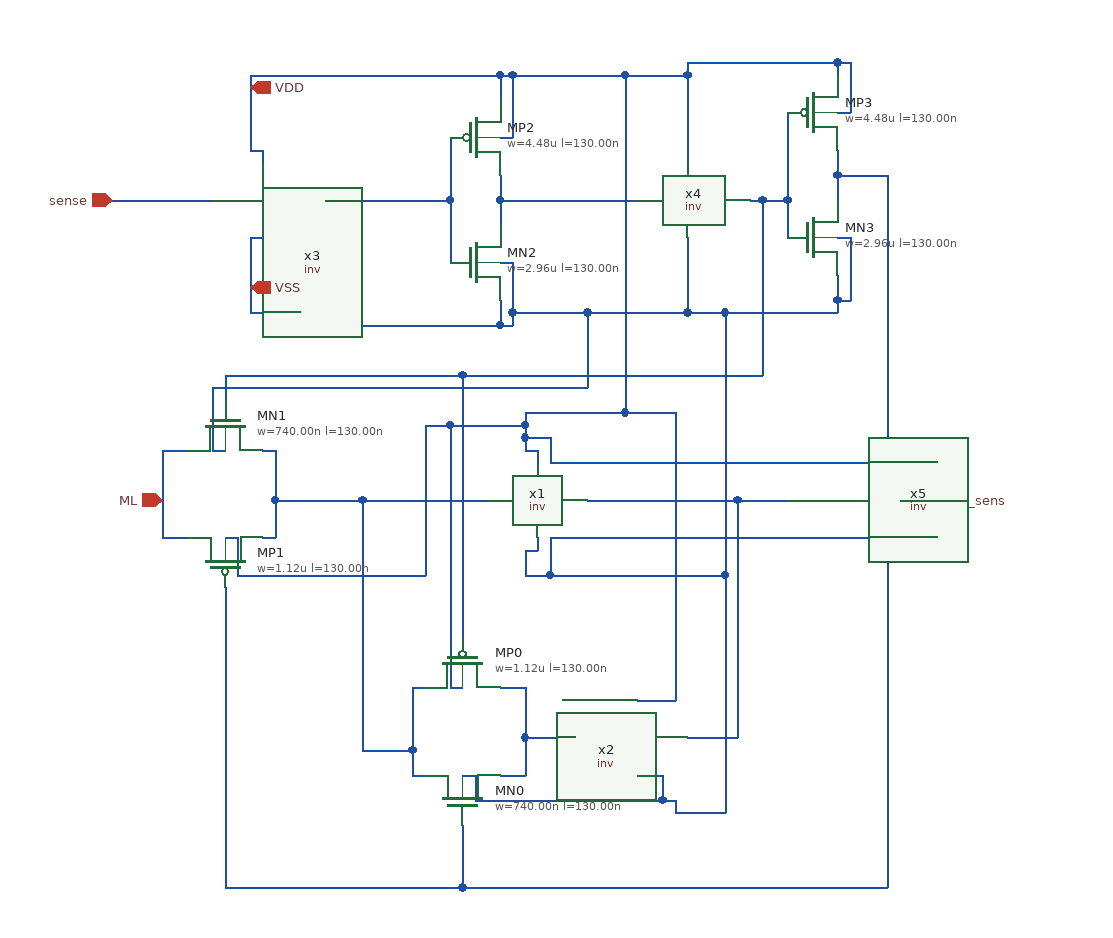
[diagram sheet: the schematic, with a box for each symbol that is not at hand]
v {xschem version=3.4.6 file_version=1.2}
G {}
K {}
V {}
S {}
E {}
N 0 260 20 260 {lab=#net1}
N 0 330 20 330 {lab=#net1}
N -70 260 -60 260 {lab=#net2}
N -70 310 -70 330 {lab=#net2}
N -70 330 -60 330 {lab=#net2}
N -30 330 -20 330 {lab=VSS}
N -40 260 -30 260 {lab=VDD}
N -110 110 -10 110 {lab=#net2}
N 70 110 190 110 {lab=#net3}
N 190 110 190 300 {lab=#net3}
N -110 110 -110 310 {lab=#net2}
N 20 60 20 70 {lab=VDD}
N -30 370 -30 420 {lab=#net4}
N 20 150 20 170 {lab=VSS}
N 140 350 140 360 {lab=VSS}
N -170 -40 -160 -40 {lab=VSS}
N -310 -130 -230 -130 {lab=sense}
N -270 140 -250 140 {lab=ML}
N -270 70 -250 70 {lab=ML}
N -190 140 -180 140 {lab=#net2}
N -190 70 -180 70 {lab=#net2}
N -230 70 -220 70 {lab=VSS}
N -220 140 -210 140 {lab=VDD}
N -210 140 -210 170 {lab=VDD}
N -220 10 -220 30 {lab=#net5}
N -180 110 -180 140 {lab=#net2}
N -270 70 -270 140 {lab=ML}
N -220 180 -220 420 {lab=#net4}
N 0 -230 10 -230 {lab=VDD}
N 0 -180 10 -180 {lab=VDD}
N 0 -80 10 -80 {lab=VSS}
N 0 -30 10 -30 {lab=VSS}
N -40 -130 -40 -80 {lab=#net6}
N 0 -230 0 -210 {lab=VDD}
N 10 -230 10 -180 {lab=VDD}
N 10 -40 10 -30 {lab=VSS}
N 0 -50 0 -30 {lab=VSS}
N -40 -180 -40 -130 {lab=#net6}
N -170 -30 0 -30 {lab=VSS}
N -170 -40 -170 -30 {lab=VSS}
N -200 -40 -170 -40 {lab=VSS}
N -200 -230 -200 -170 {lab=VDD}
N -200 -230 0 -230 {lab=VDD}
N -180 110 -110 110 {lab=#net2}
N -180 70 -180 110 {lab=#net2}
N -110 310 -70 310 {lab=#net2}
N -70 260 -70 310 {lab=#net2}
N 150 -230 150 -160 {lab=VDD}
N 100 -230 150 -230 {lab=VDD}
N 70 -40 150 -40 {lab=VSS}
N 10 -80 10 -40 {lab=VSS}
N 270 -50 270 -40 {lab=VSS}
N 270 -100 280 -100 {lab=VSS}
N 280 -100 280 -50 {lab=VSS}
N 270 -50 280 -50 {lab=VSS}
N 270 -70 270 -50 {lab=VSS}
N 150 -240 150 -230 {lab=VDD}
N 150 -240 270 -240 {lab=VDD}
N 270 -240 270 -230 {lab=VDD}
N 270 -200 280 -200 {lab=VDD}
N 280 -240 280 -200 {lab=VDD}
N 270 -240 280 -240 {lab=VDD}
N 270 -150 270 -130 {lab=#net4}
N 0 -130 0 -110 {lab=#net7}
N 230 -130 230 -100 {lab=#net5}
N 210 -130 230 -130 {lab=#net5}
N 230 -200 230 -130 {lab=#net5}
N 270 -150 310 -150 {lab=#net4}
N 270 -170 270 -150 {lab=#net4}
N 20 150 30 150 {lab=VSS}
N 30 140 30 150 {lab=VSS}
N 20 70 30 70 {lab=VDD}
N 30 70 30 80 {lab=VDD}
N -190 -170 -190 -160 {lab=VDD}
N -200 -170 -190 -170 {lab=VDD}
N -200 -100 -200 -40 {lab=VSS}
N -200 -100 -190 -100 {lab=VSS}
N 150 -100 150 -40 {lab=VSS}
N -220 420 -30 420 {lab=#net4}
N -30 10 -30 220 {lab=#net5}
N 310 -150 310 420 {lab=#net4}
N 20 40 100 40 {lab=VDD}
N 100 -230 100 40 {lab=VDD}
N 10 -230 100 -230 {lab=VDD}
N 140 40 140 270 {lab=VDD}
N 100 40 140 40 {lab=VDD}
N 140 360 180 360 {lab=VSS}
N 180 170 180 360 {lab=VSS}
N -210 170 -60 170 {lab=VDD}
N -60 50 -60 170 {lab=VDD}
N -40 50 20 50 {lab=VDD}
N 20 40 20 50 {lab=VDD}
N -230 20 -230 70 {lab=VSS}
N -230 20 70 20 {lab=VSS}
N 70 -40 70 20 {lab=VSS}
N 10 -40 70 -40 {lab=VSS}
N -20 330 -20 350 {lab=VSS}
N 130 350 140 350 {lab=VSS}
N -40 50 -40 260 {lab=VDD}
N -60 50 -40 50 {lab=VDD}
N 40 80 350 80 {lab=VDD}
N 40 60 40 80 {lab=VDD}
N 20 60 40 60 {lab=VDD}
N 20 50 20 60 {lab=VDD}
N 40 140 350 140 {lab=VSS}
N 40 140 40 170 {lab=VSS}
N 20 170 40 170 {lab=VSS}
N 180 -40 270 -40 {lab=VSS}
N 130 330 130 350 {lab=VSS}
N -20 350 130 350 {lab=VSS}
N 110 330 130 330 {lab=VSS}
N 110 270 140 270 {lab=VDD}
N 20 300 20 330 {lab=#net1}
N 20 300 60 300 {lab=#net1}
N 20 260 20 300 {lab=#net1}
N 150 300 190 300 {lab=#net3}
N -140 -130 -40 -130 {lab=#net6}
N 190 110 230 110 {lab=#net3}
N 320 110 340 110 {lab=ML_sens}
N 40 170 180 170 {lab=VSS}
N 180 -40 180 170 {lab=VSS}
N 150 -40 180 -40 {lab=VSS}
N 0 -130 110 -130 {lab=#net7}
N 0 -150 0 -130 {lab=#net7}
N -220 10 -30 10 {lab=#net5}
N -30 10 210 10 {lab=#net5}
N 210 -130 210 10 {lab=#net5}
N 200 -130 210 -130 {lab=#net5}
N -30 420 310 420 {lab=#net4}
C {inv.sym} 70 200 0 0 {name=x1}
C {sg13g2_pr/sg13_lv_pmos.sym} -30 240 1 0 {name=MP0
l=130.00n
w=1.12u
ng=1
m=1
model=sg13_lv_pmos
spiceprefix=X
}
C {sg13g2_pr/sg13_lv_nmos.sym} -30 350 3 0 {name=MN0
l=130.00n
w=740.00n
ng=1
m=1
model=sg13_lv_nmos
spiceprefix=X
}
C {sg13g2_pr/sg13_lv_pmos.sym} -220 160 3 0 {name=MP1
l=130.00n
w=1.12u
ng=1
m=1
model=sg13_lv_pmos
spiceprefix=X
}
C {sg13g2_pr/sg13_lv_nmos.sym} -220 50 1 0 {name=MN1
l=130.00n
w=740.00n
ng=1
m=1
model=sg13_lv_nmos
spiceprefix=X
}
C {sg13g2_pr/sg13_lv_nmos.sym} -20 -80 0 0 {name=MN2
l=130.00n
w=2.96u
ng=1
m=1
model=sg13_lv_nmos
spiceprefix=X
}
C {sg13g2_pr/sg13_lv_pmos.sym} -20 -180 0 0 {name=MP2
l=130.00n
w=4.48u
ng=1
m=1
model=sg13_lv_pmos
spiceprefix=X
}
C {sg13g2_pr/sg13_lv_pmos.sym} 250 -200 0 0 {name=MP3
l=130.00n
w=4.48u
ng=1
m=1
model=sg13_lv_pmos
spiceprefix=X
}
C {sg13g2_pr/sg13_lv_nmos.sym} 250 -100 0 0 {name=MN3
l=130.00n
w=2.96u
ng=1
m=1
model=sg13_lv_nmos
spiceprefix=X
}
C {inv.sym} 70 390 0 1 {name=x2}
C {inv.sym} -150 -40 0 0 {name=x3}
C {inv.sym} 190 -40 0 0 {name=x4}
C {ipin.sym} -310 -130 0 0 {name=p2 lab=sense}
C {iopin.sym} -200 -220 0 1 {name=p3 lab=VDD}
C {iopin.sym} -200 -60 0 1 {name=p4 lab=VSS}
C {ipin.sym} -270 110 0 0 {name=p5 lab=ML}
C {opin.sym} 340 110 0 0 {name=p1 lab=ML_sens}
C {inv.sym} 310 200 0 0 {name=x5}
